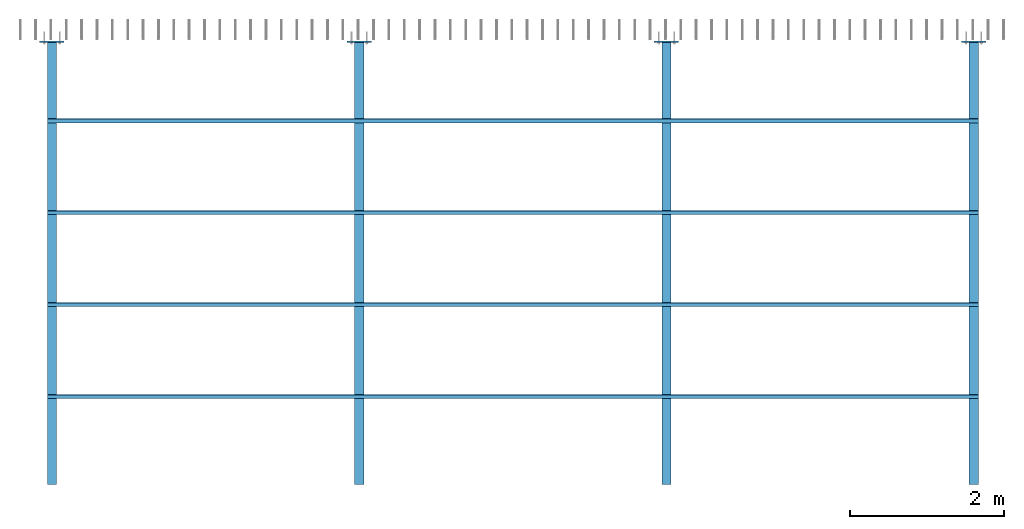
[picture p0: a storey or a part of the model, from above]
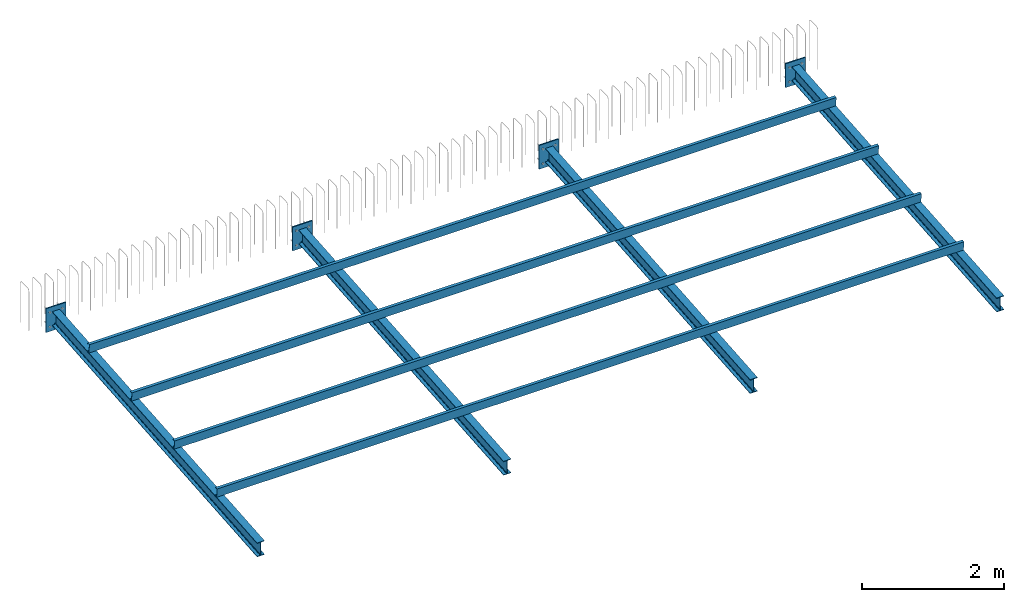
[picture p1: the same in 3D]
Properties of the parts of a building model (IFC4X3_ADD2), part 1 of 2

# File
Description: ViewDefinition [CoordinationView], RevitIdentifiers [ContentGUID: 4acb6c96-97fd-44d4-9711-2617cdbfe43d, VersionGUID: ed7fe11c-8d02-4497-8ebc-b011db3e209e, NumberOfSaves: 38], CoordinateReference [CoordinateBase: Shared Coordinates, ProjectSite: Internal]
File name: Complex_structure.ifc
Time: 2026-06-14T23:28:43+01:00
Written by: ODA SDAI 24.12
Made in: Autodesk Revit 25.4.0.32 (ENU) - IFC 25.4.0.27

# IfcProject, Complex structure
LongName: Project Name; Phase: Project Status

# IfcSite, Default
RefLatitude: 42, 21, 31, 181945; RefLongitude: -71, -3, -24, -263305; RefElevation: 0 mm
Pset_SiteCommon - Reference: Project Information
Pset_SpaceCommon - Reference: Project Information; IsExternal: no
Other - Category: Project Information; Client Name: Owner; Project Address: Enter address here; Project Issue Date: Issue Date; Project Name: Project Name; Project Number: Complex structure; Project Status: Project Status
Identity Data - Author: FJ; Building Name: Complex structure; Organization Name: QuantBIM

# IfcBuilding, Complex structure
LongName: Complex structure
Pset_BuildingCommon - Reference: Project Information; NumberOfStoreys: 8
Pset_BuildingElementProxyCommon - Reference: Project Information; IsExternal: no; sets with these values: 2
Pset_BuildingStoreyCommon - Reference: Project Information; sets with these values: 2
Other - Category: Project Information; Client Name: Owner; Project Address: Enter address here; Project Issue Date: Issue Date; Project Name: Project Name; Project Number: Complex structure; Project Status: Project Status
Identity Data - Author: FJ; Building Name: Complex structure; Organization Name: QuantBIM

# IfcBuildingStorey: Level:8mm Head (8)
In: Complex structure
Pset_BuildingStoreyCommon - Reference: 8mm Head
Pset_SpaceCommon - IsExternal: no; Reference: 8mm Head
Other - Category: Levels; Family: Level; Family and Type: Level: 8mm Head; Type: 8mm Head; Type Id: 305
Dimensions - Computation Height: 0 mm
Identity Data - Building Story: yes; Structural: no
Other(Type) - Category: Levels; Family Name: Level
Constraints(Type) - Elevation Base: Project Base Point
Graphics(Type) - Color: 0; Line Pattern: Centre; Line Weight: 1; Symbol: M_Level Head - Circle; Symbol at End 1 Default: no; Symbol at End 2 Default: yes
Identity Data(Type) - Type Name: 8mm Head
Name | LongName = Name | Elevation (mm) = Constraints, Elevation (mm)
Level -03 | Level -03 | -1200
Level -02 | Level -02 | -400
Level -01 | Level -01 | -200
Level 00 | Level 00 | 0
Level 01 | Level 01 | 3000
Level 02 | Level 02 | 4000
Level 03 | Level 03 | 4500
Level 04 | Level 04 | 5000

# IfcBeam: Construction_Beams-&-Lintels_Lindab_C-HU:Lindab C 150/1.5 (6)
Type - PredefinedType: JOIST; Material: Lindab_000_Galvanized
Type - Other - Category: Structural Framing; Family Name: Construction_Beams-&-Lintels_Lindab_C-HU
Type - Constraints - t: 1.5 mm
Type - Dimensions - Dimension: 150 mm; Flange1: 41 mm; Flange2: 47 mm; Stiffener: 15 mm; Thickness: 1.5 mm
Type - General - Brand url: http://www.lindab.com; Design country: Sweden; Edition number: 1; Manufacturer name: Lindab; Nominal height: 0 mm; Nominal width: 0 mm; Product family: Steel profiles; Product group: Purlins; Product SKU: c; QR code: http://bimobject.com/lindab/product/c; Region Europe: CZ, DK, HU, NO, PL, RO, SE, SK; Weight Net (Kg): 0
Type - Identity Data - Advanced_Design_Tool: http://www.lindab.com/lindabstructuraldesigner; Code Name: C; Installation instructions: http://www.lindab.com/global/Documents/Building%20Components%20Global/system_solution_roof_assembly_low.pdf; Manufacturer: Lindab; OmniClass Number: 23.25.30.11.14.14; OmniClass Title: Beams; Product certification: https://itsolution.lindab.com/lindabwebproductsdoc/pdf/documentation/building_components/uk/DoP/C_profiles.pdf; Product data url: https://bimobject.com/lindab/product/c; Product url: http://www.lindab.com/global/pro/downloads/certificates/pages/default.aspx#drilldown_guid:9fd857e6-9304-4852-8a1e-055bb2913d50;level:all;sub:4; Quick_Design_Tool: n/a; Section_Properties_Tool: http://ec3library.lindab.com; Technical description: http://ec3library.lindab.com/; Type Name: Lindab C 150/1.5; URL: http://www.lindab.com
Type - Materials and Finishes - Coating: n/a; Color: Natural Zinc; Material main: Galvanized steel; NCS: n/a; Quality: S350 Z275; RAL: n/a; Structural Material: Lindab_000_Galvanized
Type - Structural - Section Shape: 9
Type - Pset_BeamCommon - LoadBearing: yes
Type - Pset_ManufacturerTypeInformation - Manufacturer: Lindab
Pset_BeamCommon - IsExternal: no; Reference: Lindab C 150/1.5; Span: 12120 mm; Slope: 0 deg; Roll: 90 deg
Pset_EnvironmentalImpactIndicators - Reference: Lindab C 150/1.5; sets with these values: 2
Other - Family: Construction_Beams-&-Lintels_Lindab_C-HU; Family and Type: Construction_Beams-&-Lintels_Lindab_C-HU: Lindab C 150/1.5; LRT_Fastener: 0; Type: Lindab C 150/1.5; Type Id: 407912
Constraints - Orientation: Normal; Reference Level: Level -02; Cross-Section Rotation: 90 deg; Reference Level Elevation: -400 mm; Work Plane: Reference Plane : Szelemenek
Dimensions - Length: 12120 mm; Volume: 0.00476316 m3
Identity Data - Has Association: no
Phasing - Phase Created: New Construction
Structural - Stick Symbol Location: Center of Geometry; Cut Length: 12120 mm; Structural Usage: Joist; Weight: 0 kg
Geometric Position - End Extension: 0 mm; Join Status: Both joins enabled; Start Extension: 0 mm; y Justification: Origin; yz Justification: Uniform; z Justification: Top; z Offset Value: 0 mm; y Offset Value: -75 mm
Name (Construction_Beams-&-Lintels_Lindab_C-HU:Lindab C 150/1.5:...) | In | Host Id | End Level Offset (mm) = Start Level Offset (mm) | Elevation at Bottom (mm) | Elevation at Top (mm) | End Join Cutback (mm)
478069 | Level 02 | 478030 | 4805.5 | 4401.6 | 4554.98 | 12.7
478071 | Level 02 | 478030 | 4705.85 | 4301.94 | 4455.33 | 12.7
478073 | Level 02 | 478030 | 4606.19 | 4202.29 | 4355.68 | Geometric Position - Start Join Cutback: 12.7 mm
478180 | Level 02 | 478030 | 4506.54 | 4102.64 | 4256.02 | Geometric Position - Start Join Cutback: 12.7 mm
478247 | Level -02 |  | 4406.88 | 4002.98 | 4156.37 | 12.7 | Geometric Position - Start Join Cutback: 12.7 mm; Structural - End Attachment Type: End Elevation; Start Attachment Type: End Elevation
478413 | Level -02 |  | 4880.24 | 4476.34 | 4629.73 | 12.7

# IfcBeam: IPE:IPE140 (3)
In: Level 01
Type - PredefinedType: BEAM
Type - Other - Category: Structural Framing; Family Name: IPE
Type - Dimensions - Bolt Spacing: 0 mm
Type - Identity Data - Code Name: EURONORM 19-57; DIN 1025-5; Section Name Key: IPE140; Type Name: IPE140
Type - Structural - Section Shape: 6
Type - Structural Analysis - Torsional Moment of Inertia: 0 m4; Elastic Modulus strong axis: 0.0000773 m3; Elastic Modulus weak axis: 0.0000123 m3; Moment of Inertia strong axis: 0.00000541 m4; Moment of Inertia weak axis: 4.49e-07 m4; Nominal Weight: 126.506 kg/s2; Perimeter: 551 mm; Plastic Modulus strong axis: 0.0000883 m3; Plastic Modulus weak axis: 0.0000193 m3; Section Area: 0.00164 m2; Warping Constant: 0 m6
Type - Structural Section Geometry - Centroid Horizontal: 36.5 mm; Centroid Vertical: 70 mm; Flange Thickness: 6.9 mm; Height: 140 mm; Web Fillet: 7 mm; Web Thickness: 4.7 mm; Width: 73 mm
Type - Pset_BeamCommon - LoadBearing: yes
Description: BP{2A70AE7B-3EAF-463A-89AE-3075FF3C759C}; Material: Structural Steel - S235
Pset_BeamCommon - IsExternal: no; Roll: 0 deg; Slope: 0 deg; Reference: IPE140; Span: 4000 mm
Pset_EnvironmentalImpactIndicators - Reference: IPE140; sets with these values: 2
ProfileProperties - SectionFamily: {2A70AE7B-3EAF-463A-89AE-3075FF3C759C}BP; Section: BP{2A70AE7B-3EAF-463A-89AE-3075FF3C759C}
Other - Family: IPE; Family and Type: IPE: IPE140; Type: IPE140; Type Id: 399445
Constraints - Cross-Section Rotation: 0 deg; End Level Offset: 0 mm; Reference Level: Level 01; Start Level Offset: 0 mm; Orientation: Normal; Reference Level Elevation: 3000 mm; Work Plane: Level : Level 01
Dimensions - Elevation at Bottom: 2860 mm; Elevation at Top: 3000 mm; Length: 4000 mm; Volume: 0.00634454 m3
Identity Data - Has Association: no
Materials and Finishes - Structural Material: Structural Steel - S235
Phasing - Phase Created: New Construction
Structural - End Attachment Type: End Elevation; Start Attachment Type: End Elevation; Stick Symbol Location: Center of Geometry; Structural Usage: Girder; Coating: -; Cut Length: 3964 mm; Exact Weight: 52.246 kg; Paint Area: 2.18416 m2; Weight: 52.0389 kg
Geometric Position - Join Status: Both joins enabled; y Justification: Origin; y Offset Value: 0 mm; yz Justification: Uniform; z Justification: Top; z Offset Value: 0 mm
Name (IPE:IPE140:...)
399533
399563
399612

# IfcBeam: Round Bars:RB 20 (25)
Type - PredefinedType: BEAM; Material: Metal - Steel 50-355
Type - Other - Category: Structural Framing; Family Name: Round Bars
Type - Identity Data - Assembly Code: B10; Assembly Description: Superstructure; Code Name: EN 10060:2003; Section Name Key: RB 20; Type Name: RB 20
Type - Structural - Section Shape: 13
Type - Structural Analysis - Elastic Modulus strong axis: 0 m3; Elastic Modulus weak axis: 0 m3; Moment of Inertia strong axis: 0 m4; Moment of Inertia weak axis: 0 m4; Nominal Weight: 24.2224 kg/s2; Perimeter: 63 mm; Plastic Modulus strong axis: 0 m3; Plastic Modulus weak axis: 0 m3; Section Area: 0.000314 m2; Torsional Modulus: 0 m3; Torsional Moment of Inertia: 0 m4
Type - Structural Section Geometry - Centroid Horizontal: 10 mm; Centroid Vertical: 10 mm; Diameter: 20 mm
Type - Pset_BeamCommon - LoadBearing: yes
Classification: B10 Superstructure (Uniformat)
Pset_BeamCommon - IsExternal: no; Reference: RB 20; Roll: 0 deg
Pset_EnvironmentalImpactIndicators - Reference: RB 20; sets with these values: 2
Other - Family: Round Bars; Family and Type: Round Bars: RB 20; Type: RB 20; Type Id: 400683
Constraints - Cross-Section Rotation: 0 deg
Identity Data - Has Association: no
Materials and Finishes - Structural Material: Metal - Steel 50-355
Phasing - Phase Created: New Construction
Structural - Stick Symbol Location: Center of Geometry
Geometric Position - Join Status: Both joins enabled; y Justification: Origin; y Offset Value: 0 mm; yz Justification: Uniform; z Justification: Top; z Offset Value: 0 mm
Name (Round Bars:RB 20:...) | In | Span (mm) = Length (mm) | Slope (deg) | End Level Offset (mm) | Reference Level | Reference Level Elevation (mm) | Start Level Offset (mm) | Volume (m3) | Cut Length (mm) | End Attachment Type | Structural Usage | Weight (kg) | End Extension (mm) | End Join Cutback (mm) | Start Extension (mm) | Start Join Cutback (mm) | Orientation | Work Plane
473897 | Level 01 | 4123.1 | 14.0362 | 0 | Level 01 | 3000 | 1000 | 0.00123386 | 3927.7 | End Elevation | Girder | 9.68488 | 0 | 12.7 | 0 | 12.7 | Structural - Start Attachment Type: End Elevation
473987 | Level 01 | 4123.1 | 14.0362 | 1000 | Level 01 | 3000 | 0 | 0.00123386 | 3927.7 | End Elevation | Girder | 9.68488 | 0 | 12.7 | 0 | 12.7 | Structural - Start Attachment Type: End Elevation
474049 | Level 01 | 4123.1 | 14.0362 | 0 | Level 01 | 3000 | 1000 | 0.00123386 | 3927.7 | End Elevation | Girder | 9.68488 | 0 | 12.7 | 0 | 12.7 | Structural - Start Attachment Type: End Elevation
474135 | Level 01 | 4123.1 | 14.0362 | 1000 | Level 01 | 3000 | 0 | 0.00123386 | 3927.7 | End Elevation | Girder | 9.68488 | 0 | 12.7 | 0 | 12.7 | Structural - Start Attachment Type: End Elevation
474136 | Level 01 | 4123.1 | 14.0362 | 0 | Level 01 | 3000 | 1000 | 0.00123386 | 3927.7 | End Elevation | Girder | 9.68488 | 0 | 12.7 | 0 | 12.7 | Structural - Start Attachment Type: End Elevation
474175 | Level 01 | 4123.1 | 14.0362 | 1000 | Level 01 | 3000 | 0 | 0.00123386 | 3927.7 | End Elevation | Girder | 9.68488 | 0 | 12.7 | 0 | 12.7 | Structural - Start Attachment Type: End Elevation
474176 | Level 01 | 4123.1 | 14.0362 | 0 | Level 01 | 3000 | 1000 | 0.00123386 | 3927.7 | End Elevation | Girder | 9.68488 | 0 | 12.7 | 0 | 12.7 | Structural - Start Attachment Type: End Elevation
474847 | Level -02 | 4506.7 | 2.19258 | 4616.05 | Level -02 | -400 | 4443.63 | 0.00141575 | 4506.7 |  | Other | 11.1126 | 0 | -20.3646 | 0 | -20.1328 | Normal | Reference Plane : Merevitok
474897 | Level -02 | 4409 | 2.00187 | 4770.07 | Level -02 | -400 | 4616.05 | 0.00138509 | 4409.09 |  | Other | 10.8719 | 0 | -21.5679 | -4.91049 |  | Normal | Reference Plane : Merevitok
474934 | Level -02 | 4409 | 2.00187 | 4616.05 | Level -02 | -400 | 4770.07 | 0.00138506 | 4409 |  | Other | 10.8717 | 0 | -20.8261 | 0 |  | Normal | Reference Plane : Merevitok
474989 | Level -02 | 4466.6 | 2.11781 | 4450.99 | Level -02 | -400 | 4616.05 | 0.00140317 | 4466.63 |  | Other | 11.0138 | -4.96898 |  | 0 | -20.8261 | Normal | Reference Plane : Merevitok
475036 | Level -02 | 4466.6 | 2.11781 | 4285.93 | Level -02 | -400 | 4450.99 | 0.00140316 | 4466.6 | End Elevation | Other | 11.0137 | 0 | -19.7362 | 0 | -20.1248 | Normal | Reference Plane : Merevitok
475112 | Level -02 | 4427.8 | 2.04105 | 4285.93 | Level -02 | -400 | 4443.63 | 0.00139128 | 4428.8 | End Elevation | Other | 10.9205 | 0 | -21.6534 | 0 | -20.1328 | Normal | Reference Plane : Merevitok
475159 | Level -02 | 4409 | 2.00187 | 4770.07 | Level -02 | -400 | 4616.05 | 0.00138507 | 4409.03 |  | Other | 10.8717 | -21.5679 |  | 0 | -20.3646 | Normal | Reference Plane : Merevitok
475161 | Level -02 | 4466.6 | 2.11781 | 4450.99 | Level -02 | -400 | 4616.05 | 0.00140316 | 4466.6 |  | Other | 11.0137 | 0 | -20.1248 | 0 | -20.8261 | Normal | Reference Plane : Merevitok
475199 | Level -02 | 4506.7 | 2.19258 | 4616.05 | Level -02 | -400 | 4443.63 | 0.00141575 | 4506.7 |  | Other | 11.1126 | 0 | -20.3646 | 0 | -20.1328 | Normal | Reference Plane : Merevitok
475201 | Level -02 | 4409 | 2.00187 | 4616.05 | Level -02 | -400 | 4770.07 | 0.00138509 | 4409.1 |  | Other | 10.8719 | -4.80167 |  | 0 | -7.63229 | Normal | Reference Plane : Merevitok
475337 | Level -02 | 4506.7 | 2.19258 | 4616.05 | Level -02 | -400 | 4443.63 | 0.00141575 | 4506.7 |  | Other | 11.1126 | 0 | -20.3646 | 0 | -20.1328 | Normal | Reference Plane : Merevitok
475338 | Level -02 | 4409 | 2.00187 | 4616.05 | Level -02 | -400 | 4770.07 | 0.00138506 | 4409 |  | Other | 10.8717 | 0 | -20.8261 | -21.5679 | -7.63229 | Normal | Reference Plane : Merevitok
475387 | Level -02 | 4409 | 2.00187 | 4770.07 | Level -02 | -400 | 4616.05 | 0.00138506 | 4409 |  | Other | 10.8717 | 0 |  | 0 | -20.3646 | Normal | Reference Plane : Merevitok
475388 | Level -02 | 4466.6 | 2.11781 | 4450.99 | Level -02 | -400 | 4616.05 | 0.00140316 | 4466.6 |  | Other | 11.0137 | 0 | -20.1248 | 0 | -20.8261 | Normal | Reference Plane : Merevitok
475510 | Level -02 | 4466.6 | 2.11781 | 4285.93 | Level -02 | -400 | 4450.99 | 0.00140316 | 4466.6 | End Elevation | Other | 11.0137 | 0 | -19.7362 | 0 | -20.1248 | Normal | Reference Plane : Merevitok
475511 | Level -02 | 4427.8 | 2.04105 | 4285.93 | Level -02 | -400 | 4443.63 | 0.00139097 | 4427.8 | End Elevation | Other | 10.918 | 0 | -20.6607 | 0 | -20.1328 | Normal | Reference Plane : Merevitok
475529 | Level -02 | 4466.6 | 2.11781 | 4285.93 | Level -02 | -400 | 4450.99 | 0.0014035 | 4467.7 | End Elevation | Other | 11.0164 | 0 | -20.8126 | 0 | -20.1248 | Normal | Reference Plane : Merevitok
475530 | Level -02 | 4427.8 | 2.04105 | 4285.93 | Level -02 | -400 | 4443.63 | 0.00139097 | 4427.8 | End Elevation | Other | 10.918 | 0 | -20.6607 | 0 | -20.1328 | Normal | Reference Plane : Merevitok

# IfcBuildingElementProxy: Foundation Slab:Foundation Slab 200mm, Foundation Slab:Foundation Slab 200mm:356789
In: Level -02
Material: Concrete, Cast In Situ 200 mm
Other - Category: Structural Foundations; Family: Foundation Slab; Family and Type: Foundation Slab: Foundation Slab 200mm; Type: Foundation Slab 200mm; Type Id: 356880
Constraints - Level: Level -02; Related to Mass: no; Height Offset From Level: 200 mm
Dimensions - Area: 82.81 m2; Core Thickness: 200 mm; Elevation at Bottom: -400 mm; Elevation at Bottom Core: -400 mm; Elevation at Bottom Survey: -400 mm; Elevation at Top: -200 mm; Elevation at Top Core: -200 mm; Elevation at Top Survey: -200 mm; Length: 6370 mm; Perimeter: 38740 mm; Thickness: 200 mm; Volume: 16.562 m3; Width: 13000 mm
Identity Data - Has Association: no
Phasing - Phase Created: New Construction
Structural - Rebar Cover - Other Faces: Rebar Cover 1 <25 mm>; Structural: yes; Estimated Reinforcement Volume: 0.154037 m3; Rebar Cover - Bottom Face: Rebar Cover 1 <25 mm>; Rebar Cover - Top Face: Rebar Cover 1 <25 mm>
Other(Type) - Category: Structural Foundations; Family Name: Foundation Slab
Construction(Type) - Default Thickness: 200 mm
Dimensions(Type) - Foundation Thickness: 200 mm
Graphics(Type) - Coarse Scale Fill Color: 0
Identity Data(Type) - Type Name: Foundation Slab 200mm
Materials and Finishes(Type) - Structural Material: Concrete, Cast In Situ
Analytical Properties(Type) - Absorptance: 0.7; Roughness: 3; Heat Transfer Coefficient (U): 5.23 kg/K/s3; Thermal Mass: 302220 kg/K/s2; Thermal Resistance (R): 0.191205 s3*K/kg

# IfcColumn: HE-A Column:HEA160 (4)
In: Level -01
Type - PredefinedType: COLUMN; Material: Structural Steel - S235
Type - Other - Category: Structural Columns; Family Name: HE-A Column
Type - Dimensions - Bolt Diameter: 0 mm; Bolt Spacing: 99 mm
Type - Identity Data - Code Name: EURONORM 53-62; DIN 1025-3; Section Name Key: HEA160; Type Name: HEA160
Type - Structural - Section Shape: 8
Type - Structural Analysis - Torsional Moment of Inertia: 0 m4; Warping Constant: 0 m6; Elastic Modulus strong axis: 0.00022 m3; Elastic Modulus weak axis: 0.0000769 m3; Moment of Inertia strong axis: 0.0000167 m4; Moment of Inertia weak axis: 0.00000616 m4; Nominal Weight: 298.122 kg/s2; Perimeter: 906 mm; Plastic Modulus strong axis: 0.0002451 m3; Plastic Modulus weak axis: 0.0001176 m3; Section Area: 0.00388 m2
Type - Structural Section Geometry - Centroid Horizontal: 80 mm; Centroid Vertical: 76 mm; Flange Thickness: 9 mm; Height: 152 mm; Web Fillet: 15 mm; Web Thickness: 6 mm; Width: 160 mm
Type - Pset_ColumnCommon - LoadBearing: yes
Description: BP{7F9EABB0-F8C3-481F-A3BD-D3AADC916256}
Pset_ColumnCommon - IsExternal: no; Reference: HEA160
Pset_EnvironmentalImpactIndicators - Reference: HEA160; sets with these values: 2
ProfileProperties - SectionFamily: {7F9EABB0-F8C3-481F-A3BD-D3AADC916256}BP; Section: BP{7F9EABB0-F8C3-481F-A3BD-D3AADC916256}
Other - Family: HE-A Column; Family and Type: HE-A Column: HEA160; Type: HEA160; Type Id: 391126
Constraints - Moves With Grids: yes; Base Offset: 0 mm; Base Level: Level -01; Column Style: Vertical; Level: Level -01; Top Level: Level 02; Top Offset: 0 mm
Dimensions - Length: 4200 mm; Volume: 0.0153423 m3
Identity Data - Has Association: no
Materials and Finishes - Structural Material: Structural Steel - S235
Phasing - Phase Created: New Construction
Structural - Coating: -; Cut Length: 4170.9 mm; Exact Weight: 129.688 kg; Paint Area: 3.77883 m2; Weight: 130.446 kg
Name (HE-A Column:HEA160:...) | Column Location Mark
362460 | B-3
362442 | B-2
359729 | B-1
362476 | B-4

# IfcElementAssembly: Structural Beam System:Structural Framing System, Structural Beam System:Structural Framing System:478030
In: Level 02
PredefinedType: BEAM_GRID
Pset_ElementAssemblyCommon - Reference: Structural Framing System; sets with these values: 2
Other - Category: Structural Beam Systems; Family: Structural Beam System; Family and Type: Structural Beam System: Structural Framing System; Type: Structural Framing System; Type Id: 49026
Constraints - 3D: no; Work Plane: Reference Plane : Szelemenek
Identity Data - Tag new members in view: Structural Plan: Level 03
Phasing - Phase Created: New Construction
Pattern - Beam Type: Round Bars : RB 20; Beam Type (No Family Name): RB 20; Centerline Spacing: 1200 mm; Fixed Spacing: 1200 mm; Justification: Center; Layout Rule: Fixed Distance
Other(Type) - Category: Structural Beam Systems; Family Name: Structural Beam System
Identity Data(Type) - Type Name: Structural Framing System

# IfcFooting: Footing-Rectangular:1000 x 1000 x 800mm (4)
In: Level -02
Type - Material: Concrete - Cast-in-Place Concrete
Type - Other - Category: Structural Foundations; Family Name: Footing-Rectangular
Type - Dimensions - Foundation Thickness: 800 mm; Length: 1000 mm; Width: 1000 mm
Type - Identity Data - Type Name: 1000 x 1000 x 800mm
Pset_EnvironmentalImpactIndicators - Reference: 1000 x 1000 x 800mm; sets with these values: 4
Other - Family: Footing-Rectangular; Family and Type: Footing-Rectangular: 1000 x 1000 x 800mm; Type: 1000 x 1000 x 800mm; Type Id: 356662
Constraints - Height Offset From Level: 0 mm; Host: Level : Level -02; Level: Level -02; Moves With Grids: yes
Dimensions - Area: 1 m2; Elevation at Bottom: -1200 mm; Elevation at Bottom Survey: -1200 mm; Elevation at Top: -400 mm; Elevation at Top Survey: -400 mm; Volume: 0.8 m3
Identity Data - Has Association: no
Materials and Finishes - Structural Material: Concrete - Cast-in-Place Concrete
Phasing - Phase Created: New Construction
Structural - Rebar Cover - Bottom Face: Rebar Cover 2 <40 mm>; Rebar Cover - Other Faces: Rebar Cover 2 <40 mm>
Name (Footing-Rectangular:1000 x 1000 x 800mm:...) | Estimated Reinforcement Volume (m3)
355354 | 0.00298749
355619 | 0.00654463
355704 | 0.00477191
355767 | 0.00477191

# IfcFooting: Wall Foundation:Bearing Footing 800 x 800mm, Wall Foundation:Bearing Footing 800 x 800mm:356264
In: Level -03
Type - PredefinedType: STRIP_FOOTING
Type - Other - Category: Structural Foundations; Family Name: Wall Foundation
Type - Dimensions - Default End Extension Length: 0 mm; Do Not Break At Inserts: no; Foundation Thickness: 800 mm; Width: 800 mm
Type - Identity Data - Type Name: Bearing Footing 800 x 800mm
Type - Materials and Finishes - Structural Material: Concrete, Cast In Situ
Type - Structural - Structural Usage: Bearing
Material: Concrete, Cast In Situ
Pset_EnvironmentalImpactIndicators - Reference: Bearing Footing 800 x 800mm; sets with these values: 4
Other - Family: Wall Foundation; Family and Type: Wall Foundation: Bearing Footing 800 x 800mm; Type: Bearing Footing 800 x 800mm; Type Id: 355989
Constraints - Eccentricity: 0 mm
Dimensions - Area: 10.4 m2; Elevation at Bottom: -1200 mm; Elevation at Bottom Survey: -1200 mm; Elevation at Top: -400 mm; Elevation at Top Survey: -400 mm; Length: 13000 mm; Volume: 8.32 m3
Identity Data - Has Association: no
Phasing - Phase Created: New Construction
Structural - Rebar Cover - Bottom Face: Rebar Cover 2 <40 mm>; Rebar Cover - Other Faces: Rebar Cover 2 <40 mm>; Estimated Reinforcement Volume: 0.06958 m3; Rebar Cover - Top Face: Rebar Cover 2 <40 mm>

# IfcMechanicalFastener: Anchor_Bolt#1 (8)
Name | In | NominalDiameter (mm) | NominalLength (mm)
4 x  | Level 02 | 20 | 170
4 x  | Level -03 | 19.05 | 304.8

# IfcMechanicalFastener: Bolt#1 (10)
Name | In | NominalDiameter (mm) | NominalLength (mm)
4 x  | Level 01 | 16 | 55
6 x  | Level 00 | 12 | 45

# IfcMechanicalFastener: Bolt#2 (10)
Name | In | NominalDiameter (mm) | NominalLength (mm)
4 x  | Level 01 | 16 | 55
6 x  | Level 00 | 12 | 45

# IfcMechanicalFastener: Bolt#3 (4)
In: Level 01
NominalDiameter: 16 mm; NominalLength: 55 mm

# IfcMechanicalFastener: Bolt#4 (4)
In: Level 01
NominalDiameter: 16 mm; NominalLength: 55 mm

# IfcMechanicalFastener: Bolt#5 (10)
Name | In | NominalDiameter (mm) | NominalLength (mm)
4 x  | Level 01 | 16 | 55
6 x  | Level 00 | 12 | 45

# IfcMechanicalFastener: Bolt#6 (10)
Name | In | NominalDiameter (mm) | NominalLength (mm)
4 x  | Level 01 | 16 | 55
6 x  | Level 00 | 12 | 45

# IfcMechanicalFastener: Bolt#7 (4)
In: Level 01
NominalDiameter: 16 mm; NominalLength: 55 mm

# IfcMechanicalFastener: Bolt#8 (4)
In: Level 01
NominalDiameter: 16 mm; NominalLength: 55 mm

# IfcMember: Haunch (4)
In: Level 01
Description: BP{96DF68AE-9A4C-428B-985C-CF8941B73864}
ProfileProperties - SectionFamily: {96DF68AE-9A4C-428B-985C-CF8941B73864}BP; Section: BP{96DF68AE-9A4C-428B-985C-CF8941B73864}

# IfcMember: IPE-Beams:IPE240 (4)
In: Level 02
Type - PredefinedType: MEMBER; Material: Structural Steel - S235
Type - Other - Category: Structural Framing; Family Name: IPE-Beams
Type - Dimensions - bf: 120 mm; d: 240 mm; k: 24.8 mm; tf: 9.8 mm; tr: 15 mm; tw: 6.2 mm
Type - Identity Data - Type Name: IPE240
Type - Structural - A: 0.00391162 m2; Section Shape: 0; W: 0.301125
Type - Pset_MemberCommon - LoadBearing: yes
Description: BP{96DF68AE-9A4C-428B-985C-CF8941B73864}
Pset_EnvironmentalImpactIndicators - Reference: IPE240
Pset_MemberCommon - IsExternal: no; Roll: 0 deg; Reference: IPE240; Span: 5870 mm; Slope: 4.76387 deg
ProfileProperties - SectionFamily: {96DF68AE-9A4C-428B-985C-CF8941B73864}BP; Section: BP{96DF68AE-9A4C-428B-985C-CF8941B73864}
Other - Family: IPE-Beams; Family and Type: IPE-Beams: IPE240; Type: IPE240; Type Id: 362347
Constraints - Cross-Section Rotation: 0 deg; Start Level Offset: 0 mm; End Level Offset: 487.5 mm; Reference Level: Level 02; Reference Level Elevation: 4000 mm
Dimensions - Length: 5870 mm; Volume: 0.0214703 m3
Identity Data - Has Association: no
Materials and Finishes - Structural Material: Structural Steel - S235
Phasing - Phase Created: New Construction
Structural - Stick Symbol Location: Center of Geometry; Structural Usage: Girder; Weight: 0 kg; Coating: -; Cut Length: 5793.94 mm; Exact Weight: 181.626 kg; Paint Area: 5.49034 m2
Geometric Position - Join Status: Both joins enabled; y Justification: Origin; y Offset Value: 0 mm; yz Justification: Uniform; z Justification: Top; z Offset Value: 0 mm
Name (IPE-Beams:IPE240:...)
464337 | Structural - Start Attachment Type: End Elevation
473112
473148
473183 | Structural - Start Attachment Type: End Elevation

# IfcOpeningElement, Basic Wall:Generic - 300mm:6291
In: Level -02
PredefinedType: OPENING
Pset_EnvironmentalImpactIndicators - Reference: Generic - 300mm; sets with these values: 2
Other - Category: Lines: <Sketch>
Dimensions - Length: 3200 mm

# IfcPlate: Baseplate (8)
Description: -
Pset_PlateCommon - Reference: Not defined; IsExternal: no; LoadBearing: no
Name | In | Material
4 x Baseplate | Level 02 | Metal Stud Layer 20 mm
4 x Baseplate | Level -02 | Metal Stud Layer 25.4 mm

# IfcPlate: Coverplate (4)
In: Level 01
Description: -; Material: Metal Stud Layer 10 mm
Pset_PlateCommon - Reference: Not defined; IsExternal: no; LoadBearing: no

# IfcPlate: Endplate (10)
Description: -
Pset_PlateCommon - Reference: Not defined; IsExternal: no; LoadBearing: no
Name | In | Material
4 x Endplate | Level 01 | Metal Stud Layer 20 mm
6 x Endplate | Level 00 | Metal Stud Layer 15 mm

# IfcPlate: Stiffener#14 (4)
In: Level 01
Description: -; Material: Metal Stud Layer 10 mm
Pset_PlateCommon - Reference: Not defined; IsExternal: no; LoadBearing: no

# IfcPlate: Stiffener#2 (8)
In: Level 01
Description: -; Material: Metal Stud Layer 10 mm
Pset_PlateCommon - Reference: Not defined; IsExternal: no; LoadBearing: no

# IfcPlate: Stiffener#3 (4)
In: Level 01
Description: -; Material: Metal Stud Layer 10 mm
Pset_PlateCommon - Reference: Not defined; IsExternal: no; LoadBearing: no

# IfcPlate: Stiffener#5 (4)
In: Level -01
Description: -; Material: Metal Stud Layer 20 mm
Pset_PlateCommon - Reference: Not defined; IsExternal: no; LoadBearing: no

# IfcPlate: Stiffener#6 (4)
In: Level -01
Description: -; Material: Metal Stud Layer 20 mm
Pset_PlateCommon - Reference: Not defined; IsExternal: no; LoadBearing: no

# IfcReinforcingBar: Rebar Bar:10mm (34)
Type - Other - Category: Structural Rebar; Family Name: Rebar Bar
Type - Construction - Deformation: Deformed
Type - Dimensions - Bar Diameter: 10 mm; Maximum Bend Radius: 18000 mm; Model Bar Diameter: 10 mm; Standard Bend Diameter: 80 mm; Standard Hook Bend Diameter: 80 mm; Stirrup/Tie Bend Diameter: 50 mm
Type - Identity Data - Type Name: 10mm
Type - Materials and Finishes - Material: Steel Rebar - B500A, B or C
Material: Steel Rebar - B500A, B or C
Pset_ElementComponentCommon - Reference: 10mm; sets with these values: 2
Rebar Schedule - Deformation: Deformed; G: 0 mm; Geometry: Shape Driven; Bar Diameter: 10 mm; Family: Rebar Bar; Family and Type: Rebar Bar: 10mm; Material: Steel Rebar - B500A, B or C
Other - Family: Rebar Bar; Family and Type: Rebar Bar: 10mm; Type: 10mm; Type Id: 375225
Construction - Geometry: Shape Driven; Hook Rotation At End: 0 deg; Hook Rotation At Start: 0 deg; Modified Rebar Set: no; Override Hook Lengths: no; Rebar Constraint Status: Enabled; Staggered Set: no
Dimensions - G: 0 mm; H: 0 mm; J: 0 mm
Phasing - Phase Created: New Construction
Rebar Set - Distribution Type: Uniform; Layout Rule: Number with Spacing
Name (Rebar Bar:10mm :...) | In | Rebar Schedule, A (mm) = Dimensions, A (mm) | Rebar Schedule, B (mm) = Dimensions, B (mm) | Rebar Schedule, Bar Length (mm) = Dimensions, Bar Length (mm) = Maximum Bar Length (mm) = Minimum Bar Length (mm) | Rebar Schedule, C (mm) = Dimensions, C (mm) | Rebar Schedule, D (mm) = Dimensions, D (mm) | Rebar Schedule, E (mm) = Dimensions, E (mm) | Rebar Schedule, F (mm) = Dimensions, F (mm) | Rebar Schedule, H1 (mm) = Rebar Schedule, H2 (mm) = Dimensions, H1 (mm) = Dimensions, H2 (mm) | Bend Diameter (mm) | Maximum Rebar Number = Minimum Rebar Number = Rebar Number | Schedule Mark | Shape | Style | R (mm) | Length of each bar (mm) | Total Bar Length (mm) | Host Category | Quantity = Quantity By Rebar Set | Spacing (mm) | Estimated Reinforcement Volume (m3) = Reinforcement Volume (m3)
 Shape 52:375177 | Level -03 | 940 | 939.3 | 3881.34 | 95 | 95 | 1180 | 1000 | 95.6858 | 50 | 3 | 1 | 52 | Stirrup / Tie | 0 | 3881.1 | 7762.69 | Structural Foundation | 2 | 200 | 0.00060968 | Rebar Schedule - Hook At End: Stirrup/Tie Seismic - 135 deg.; Hook At Start: Stirrup/Tie Seismic - 135 deg.; Construction - Hook At End: Stirrup/Tie Seismic - 135 deg.; Hook At Start: Stirrup/Tie Seismic - 135 deg.; Stirrup/Tie Attachment: Interior Face of Cover Reference; Dimensions - Standard Bend Diameter: 50 mm
 Shape 21:377551 | Level -03 | 400 | 720 | 1461.37 | 400 | 0 | 0 | 0 | 0 | 80 | 7 | 2 | 21 | Standard | 0 | 1460 | 94989.2 | Structural Foundation | 65 | 200 | 0.00746043
 Shape 52:379061 | Level -03 | 935 | 244 | 2480.74 | 95 | 95 | 1180 | 1000 | 95.6858 | 50 | 11 | 2 | 52 | Stirrup / Tie | 0 | 2480.5 | 86826 | Structural Foundation | 35 | 200 | 0.0068193 | Rebar Schedule - Hook At End: Stirrup/Tie Seismic - 135 deg.; Hook At Start: Stirrup/Tie Seismic - 135 deg.; Construction - Hook At End: Stirrup/Tie Seismic - 135 deg.; Hook At Start: Stirrup/Tie Seismic - 135 deg.; Stirrup/Tie Attachment: Interior Face of Cover Reference; Dimensions - Standard Bend Diameter: 50 mm
 Shape 21:381630 | Level -03 | 198 | 920 | 1257.37 | 198 | 0 | 0 | 0 | 0 | 80 | 19 | 1 | 21 | Standard | 0 | 1256 | 2514.74 | Structural Foundation | 2 | 400 | 0.000197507
 Shape 21:381802 | Level -03 | 199 | 918 | 1257.37 | 199 | 0 | 0 | 0 | 0 | 80 | 18 | 1 | 21 | Standard | 0 | 1256 | 2514.74 | Structural Foundation | 2 | 400 | 0.000197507
 Shape 52:381964 | Level -03 | 443.637 | 440 | 1890.02 | 95 | 95 | 1180 | 1000 | 95.6858 | 50 | 17 | 1 | 52 | Stirrup / Tie | 0 | 1889.77 | 3780.03 | Structural Foundation | 2 | 200 | 0.000296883 | Rebar Schedule - Hook At End: Stirrup/Tie Seismic - 135 deg.; Hook At Start: Stirrup/Tie Seismic - 135 deg.; Construction - Hook At End: Stirrup/Tie Seismic - 135 deg.; Hook At Start: Stirrup/Tie Seismic - 135 deg.; Stirrup/Tie Attachment: Interior Face of Cover Reference; Dimensions - Standard Bend Diameter: 50 mm
 Shape 12:383578 | Level -02 | 120 | 6319 | 6405.39 | 0 | 0 | 0 | 0 | 0 | 80 | 22 | 3 | 12 | Standard | 50 | 6405.5 | 211378 | Structural Foundation | 33 | 400 | 0.0166016
 Shape 12:384593 | Level -02 | 150 | 7000 | 7116.39 | 0 | 0 | 0 | 0 | 0 | 80 | 23 | 3 | 12 | Standard | 50 | 7116.5 | 113862 | Structural Foundation | 16 | 400 | 0.00894272
 Shape 12:385066 | Level -02 | 120 | 7000 | 7086.39 | 0 | 0 | 0 | 0 | 0 | 80 | 53 | 3 | 12 | Standard | 50 | 7086.5 | 113382 | Structural Foundation | 16 | 400 | 0.00890503
 Shape 52:385731 | Level -03 | 940 | 939.3 | 3881.34 | 95 | 95 | 1180 | 1000 | 95.6858 | 50 | 3 | 1 | 52 | Stirrup / Tie | 0 | 3881.1 | 7762.69 | Structural Foundation | 2 | 200 | 0.00060968 | Rebar Schedule - Hook At End: Stirrup/Tie Seismic - 135 deg.; Hook At Start: Stirrup/Tie Seismic - 135 deg.; Construction - Hook At End: Stirrup/Tie Seismic - 135 deg.; Hook At Start: Stirrup/Tie Seismic - 135 deg.; Stirrup/Tie Attachment: Interior Face of Cover Reference; Dimensions - Standard Bend Diameter: 50 mm
 Shape 21:385734 | Level -03 | 198 | 920 | 1257.37 | 198 | 0 | 0 | 0 | 0 | 80 | 19 | 1 | 21 | Standard | 0 | 1256 | 2514.74 | Structural Foundation | 2 | 400 | 0.000197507
 Shape 21:385735 | Level -03 | 199 | 918 | 1257.37 | 199 | 0 | 0 | 0 | 0 | 80 | 18 | 1 | 21 | Standard | 0 | 1256 | 2514.74 | Structural Foundation | 2 | 300 | 0.000197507
 Shape 52:385736 | Level -03 | 443.637 | 440 | 1890.02 | 95 | 95 | 1180 | 1000 | 95.6858 | 50 | 17 | 1 | 52 | Stirrup / Tie | 0 | 1889.77 | 3780.03 | Structural Foundation | 2 | 200 | 0.000296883 | Rebar Schedule - Hook At End: Stirrup/Tie Seismic - 135 deg.; Hook At Start: Stirrup/Tie Seismic - 135 deg.; Construction - Hook At End: Stirrup/Tie Seismic - 135 deg.; Hook At Start: Stirrup/Tie Seismic - 135 deg.; Stirrup/Tie Attachment: Interior Face of Cover Reference; Dimensions - Standard Bend Diameter: 50 mm
 Shape 52:385758 | Level -03 | 940 | 939.3 | 3881.34 | 95 | 95 | 1180 | 1000 | 95.6858 | 50 | 3 | 1 | 52 | Stirrup / Tie | 0 | 3881.1 | 7762.69 | Structural Foundation | 2 | 200 | 0.00060968 | Rebar Schedule - Hook At End: Stirrup/Tie Seismic - 135 deg.; Hook At Start: Stirrup/Tie Seismic - 135 deg.; Construction - Hook At End: Stirrup/Tie Seismic - 135 deg.; Hook At Start: Stirrup/Tie Seismic - 135 deg.; Stirrup/Tie Attachment: Interior Face of Cover Reference; Dimensions - Standard Bend Diameter: 50 mm
 Shape 21:385761 | Level -03 | 198 | 920 | 1257.37 | 198 | 0 | 0 | 0 | 0 | 80 | 19 | 1 | 21 | Standard | 0 | 1256 | 2514.74 | Structural Foundation | 2 | 400 | 0.000197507
 Shape 21:385762 | Level -03 | 199 | 918 | 1257.37 | 199 | 0 | 0 | 0 | 0 | 80 | 18 | 1 | 21 | Standard | 0 | 1256 | 2514.74 | Structural Foundation | 2 | 400 | 0.000197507
 Shape 52:385763 | Level -03 | 443.637 | 440 | 1890.02 | 95 | 95 | 1180 | 1000 | 95.6858 | 50 | 17 | 1 | 52 | Stirrup / Tie | 0 | 1889.77 | 3780.03 | Structural Foundation | 2 | 200 | 0.000296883 | Rebar Schedule - Hook At End: Stirrup/Tie Seismic - 135 deg.; Hook At Start: Stirrup/Tie Seismic - 135 deg.; Construction - Hook At End: Stirrup/Tie Seismic - 135 deg.; Hook At Start: Stirrup/Tie Seismic - 135 deg.; Stirrup/Tie Attachment: Interior Face of Cover Reference; Dimensions - Standard Bend Diameter: 50 mm
 Shape 52:385781 | Level -03 | 940 | 939.3 | 3881.34 | 95 | 95 | 1180 | 1000 | 95.6858 | 50 | 3 | 1 | 52 | Stirrup / Tie | 0 | 3881.1 | 7762.69 | Structural Foundation | 2 | 200 | 0.00060968 | Rebar Schedule - Hook At End: Stirrup/Tie Seismic - 135 deg.; Hook At Start: Stirrup/Tie Seismic - 135 deg.; Construction - Hook At End: Stirrup/Tie Seismic - 135 deg.; Hook At Start: Stirrup/Tie Seismic - 135 deg.; Stirrup/Tie Attachment: Interior Face of Cover Reference; Dimensions - Standard Bend Diameter: 50 mm
 Shape 21:385784 | Level -03 | 198 | 920 | 1257.37 | 198 | 0 | 0 | 0 | 0 | 80 | 19 | 1 | 21 | Standard | 0 | 1256 | 2514.74 | Structural Foundation | 2 | 400 | 0.000197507
 Shape 21:385785 | Level -03 | 199 | 918 | 1257.37 | 199 | 0 | 0 | 0 | 0 | 80 | 18 | 1 | 21 | Standard | 0 | 1256 | 2514.74 | Structural Foundation | 2 | 400 | 0.000197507
 Shape 52:385786 | Level -03 | 443.637 | 440 | 1890.02 | 95 | 95 | 1180 | 1000 | 95.6858 | 50 | 17 | 1 | 52 | Stirrup / Tie | 0 | 1889.77 | 3780.03 | Structural Foundation | 2 | 200 | 0.000296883 | Rebar Schedule - Hook At End: Stirrup/Tie Seismic - 135 deg.; Hook At Start: Stirrup/Tie Seismic - 135 deg.; Construction - Hook At End: Stirrup/Tie Seismic - 135 deg.; Hook At Start: Stirrup/Tie Seismic - 135 deg.; Stirrup/Tie Attachment: Interior Face of Cover Reference; Dimensions - Standard Bend Diameter: 50 mm
 Shape 21:387282 | Level 02 | 720 | 250 | 1631.37 | 720 | 0 | 0 | 0 | 0 | 80 | 31 | 4 | 21 | Standard | 0 | 1630 | 106039 | Wall | 65 | 200 | 0.0083283
 Shape 21:391922 | Level -01 | 720 | 224 | 1605.37 | 720 | 0 | 0 | 0 | 0 | 80 | 42 | 4 | 21 | Standard | 0 | 1604 | 41739.7 | Wall | 26 | 200 | 0.00327823
 Shape 21:392317 | Level 01 | 720 | 224 | 1605.37 | 720 | 0 | 0 | 0 | 0 | 80 | 42 | 4 | 21 | Standard | 0 | 1604 | 16053.7 | Wall | 10 | 200 | 0.00126086
 Shape 21:392416 | Level -01 | 720 | 224 | 1605.37 | 720 | 0 | 0 | 0 | 0 | 80 | 42 | 4 | 21 | Standard | 0 | 1604 | 25685.9 | Wall | 16 | 200 | 0.00201737
 Shape 00:395647 | Level -03 | 12000 | 0 | 12000 | 0 | 0 | 0 | 0 | 0 | 80 | 48 | 2 | 00 | Standard | 0 | 12000 | 48000 | Structural Foundation | 4 | 200 | 0.00376991
 Shape 00:395772 | Level -03 | 12000 | 0 | 12000 | 0 | 0 | 0 | 0 | 0 | 80 | 48 | 2 | 00 | Standard | 0 | 12000 | 48000 | Structural Foundation | 4 | 200 | 0.00376991
 Shape 00:395807 | Level -02 | 12000 | 0 | 12000 | 0 | 0 | 0 | 0 | 0 | 80 | 48 | 2 | 00 | Standard | 0 | 12000 | 48000 | Structural Foundation | 4 | 200 | 0.00376991
 Shape 21:395938 | Level -03 | 910 | 721.873 | 2483.25 | 910 | 0 | 0 | 0 | 0 | 80 | 50 | 2 | 21 | Standard | 0 | 2481.87 | 9932.98 | Structural Foundation | 4 | 200 | 0.000780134
 Shape 21:396326 | Level -03 | 900 | 706 | 2447.37 | 900 | 0 | 0 | 0 | 0 | 80 | 49 | 2 | 21 | Standard | 0 | 2446 | 9789.49 | Structural Foundation | 4 | 200 | 0.000768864
 Shape 21:396605 | Level -03 | 910 | 721.873 | 2483.25 | 910 | 0 | 0 | 0 | 0 | 80 | 50 | 2 | 21 | Standard | 0 | 2481.87 | 9932.98 | Structural Foundation | 4 | 200 | 0.000780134
 Shape 21:396606 | Level -03 | 900 | 706 | 2447.37 | 900 | 0 | 0 | 0 | 0 | 80 | 49 | 2 | 21 | Standard | 0 | 2446 | 9789.49 | Structural Foundation | 4 | 200 | 0.000768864
 Shape 12:396876 | Level -02 | 140 | 7000 | 7106.39 | 0 | 0 | 0 | 0 | 0 | 80 | 26 | 3 | 12 | Standard | 50 | 7106.5 | 14212.8 | Structural Foundation | 2 | 180 | 0.00111627
 Shape 12:397622 | Level -02 | 140 | 7000 | 7106.39 | 0 | 0 | 0 | 0 | 0 | 80 | 26 | 3 | 12 | Standard | 50 | 7106.5 | 14212.8 | Wall | 2 | 180 | 0.00111627

# IfcReinforcingBar: Rebar Bar:12mm (44)
Type - Other - Category: Structural Rebar; Family Name: Rebar Bar
Type - Construction - Deformation: Deformed
Type - Dimensions - Bar Diameter: 12 mm; Maximum Bend Radius: 18000 mm; Model Bar Diameter: 12 mm; Standard Bend Diameter: 80 mm; Standard Hook Bend Diameter: 80 mm; Stirrup/Tie Bend Diameter: 50 mm
Type - Identity Data - Type Name: 12mm
Type - Materials and Finishes - Material: Steel Rebar - B500A, B or C
Material: Steel Rebar - B500A, B or C
Pset_ElementComponentCommon - Reference: 12mm; sets with these values: 2
Rebar Schedule - Bar Diameter: 12 mm; Deformation: Deformed; Family: Rebar Bar; Family and Type: Rebar Bar: 12mm; G: 0 mm; Geometry: Shape Driven; Material: Steel Rebar - B500A, B or C
Other - Family: Rebar Bar; Family and Type: Rebar Bar: 12mm; Type: 12mm; Type Id: 374903
Construction - Geometry: Shape Driven; Hook Rotation At End: 0 deg; Hook Rotation At Start: 0 deg; Modified Rebar Set: no; Override Hook Lengths: no; Rebar Constraint Status: Enabled; Staggered Set: no
Dimensions - G: 0 mm; H: 0 mm; J: 0 mm
Phasing - Phase Created: New Construction
Rebar Set - Distribution Type: Uniform; Layout Rule: Number with Spacing
Name (Rebar Bar:12mm :...) | In | Rebar Schedule, A (mm) = Dimensions, A (mm) | Rebar Schedule, B (mm) = Dimensions, B (mm) | Rebar Schedule, Bar Length (mm) = Dimensions, Bar Length (mm) = Maximum Bar Length (mm) = Minimum Bar Length (mm) | Rebar Schedule, C (mm) = Dimensions, C (mm) | Rebar Schedule, D (mm) = Dimensions, D (mm) | Rebar Schedule, E (mm) = Dimensions, E (mm) | Rebar Schedule, F (mm) = Dimensions, F (mm) | Rebar Schedule, H1 (mm) = Rebar Schedule, H2 (mm) = Dimensions, H1 (mm) = Dimensions, H2 (mm) | Bend Diameter (mm) | Maximum Rebar Number = Minimum Rebar Number = Rebar Number | Schedule Mark | Shape | Style | Length of each bar (mm) | R (mm) | Total Bar Length (mm) | Host Category | Quantity = Quantity By Rebar Set | Spacing (mm) | Estimated Reinforcement Volume (m3) = Reinforcement Volume (m3)
 Shape 21:374509 | Level -03 | 388 | 920 | 1632.51 | 388 | 0 | 0 | 0 | 0 | 80 | 2 | 1 | 21 | Standard | 1632 | 0 | 8162.57 | Structural Foundation | 5 | 200 | 0.000923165
 Shape 21:374615 | Level -03 | 399.65 | 919.3 | 1655.11 | 399.65 | 0 | 0 | 0 | 0 | 80 | 1 | 1 | 21 | Standard | 1654.6 | 0 | 8275.57 | Structural Foundation | 5 | 200 | 0.000935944
 Shape 21:375851 | Level -03 | 600 | 720 | 1856.51 | 600 | 0 | 0 | 0 | 0 | 80 | 4 | 2 | 21 | Standard | 1856 | 0 | 120673 | Structural Foundation | 65 | 200 | 0.0136478
 Shape 52:380476 | Level -03 | 925 | 420 | 2830.17 | 109 | 109 | 1180 | 1000 | 108.042 | 50 | 20 | 1 | 52 | Stirrup / Tie | 2834.5 | 0 | 8490.5 | Structural Foundation | 3 | 150 | 0.000960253 | Rebar Schedule - Hook At End: Stirrup/Tie Seismic - 135 deg.; Hook At Start: Stirrup/Tie Seismic - 135 deg.; Construction - Hook At End: Stirrup/Tie Seismic - 135 deg.; Hook At Start: Stirrup/Tie Seismic - 135 deg.; Stirrup/Tie Attachment: Interior Face of Cover Reference; Dimensions - Standard Bend Diameter: 50 mm
 Shape 52:381113 | Level -03 | 923 | 420 | 2826.17 | 109 | 109 | 1180 | 1000 | 108.042 | 50 | 13 | 1 | 52 | Stirrup / Tie | 2830.5 | 0 | 5652.34 | Structural Foundation | 2 | 200 | 0.000639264 | Rebar Schedule - Hook At End: Stirrup/Tie Seismic - 135 deg.; Hook At Start: Stirrup/Tie Seismic - 135 deg.; Construction - Hook At End: Stirrup/Tie Seismic - 135 deg.; Hook At Start: Stirrup/Tie Seismic - 135 deg.; Stirrup/Tie Attachment: Interior Face of Cover Reference; Dimensions - Standard Bend Diameter: 50 mm
 Shape 12:383577 | Level -02 | 6320 | 120 | 6403.96 | 0 | 0 | 0 | 0 | 0 | 80 | 21 | 3 | 12 | Standard | 6404.1 | 50 | 416258 | Structural Foundation | 65 | 200 | 0.0470776
 Shape 21:383880 | Level -02 | 120 | 6621 | 6797.51 | 120 | 0 | 0 | 0 | 0 | 80 | 52 | 3 | 21 | Standard | 6797 | 0 | 13595 | Structural Foundation | 2 | 200 | 0.00153756
 Shape 21:383941 | Level -02 | 120 | 6621 | 6827.51 | 150 | 0 | 0 | 0 | 0 | 80 | 54 | 3 | 21 | Standard | 6827 | 0 | 13655 | Structural Foundation | 2 | 200 | 0.00154435
 Shape 21:383959 | Level -02 | 120 | 6621 | 6797.51 | 120 | 0 | 0 | 0 | 0 | 80 | 52 | 3 | 21 | Standard | 6797 | 0 | 13595 | Structural Foundation | 2 | 200 | 0.00153756
 Shape 21:383973 | Level -02 | 120 | 6621 | 6797.51 | 120 | 0 | 0 | 0 | 0 | 80 | 52 | 3 | 21 | Standard | 6797 | 0 | 13595 | Structural Foundation | 2 | 200 | 0.00153756
 Shape 12:384594 | Level -02 | 7000 | 150 | 7113.96 | 0 | 0 | 0 | 0 | 0 | 80 | 24 | 3 | 12 | Standard | 7114.1 | 50 | 220533 | Structural Foundation | 31 | 200 | 0.0249417
 Shape 12:385067 | Level -02 | 7000 | 120 | 7083.96 | 0 | 0 | 0 | 0 | 0 | 80 | 25 | 3 | 12 | Standard | 7084.1 | 50 | 219603 | Structural Foundation | 31 | 200 | 0.0248365
 Shape 21:385219 | Level -02 | 898 | 150 | 1882.51 | 898 | 0 | 0 | 0 | 0 | 80 | 27 | 3 | 21 | Standard | 1882 | 0 | 122363 | Structural Foundation | 65 | 200 | 0.013839
 Shape 21:385727 | Level -03 | 388 | 920 | 1632.51 | 388 | 0 | 0 | 0 | 0 | 80 | 2 | 1 | 21 | Standard | 1632 | 0 | 8162.57 | Structural Foundation | 5 | 200 | 0.000923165
 Shape 21:385729 | Level -03 | 410 | 919.3 | 1675.81 | 410 | 0 | 0 | 0 | 0 | 80 | 28 | 1 | 21 | Standard | 1675.3 | 0 | 8379.07 | Structural Foundation | 5 | 200 | 0.00094765
 Shape 52:385732 | Level -03 | 925 | 420 | 2830.17 | 109 | 109 | 1180 | 1000 | 108.042 | 50 | 20 | 1 | 52 | Stirrup / Tie | 2834.5 | 0 | 8490.5 | Structural Foundation | 3 | 150 | 0.000960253 | Rebar Schedule - Hook At End: Stirrup/Tie Seismic - 135 deg.; Hook At Start: Stirrup/Tie Seismic - 135 deg.; Construction - Hook At End: Stirrup/Tie Seismic - 135 deg.; Hook At Start: Stirrup/Tie Seismic - 135 deg.; Stirrup/Tie Attachment: Interior Face of Cover Reference; Dimensions - Standard Bend Diameter: 50 mm
 Shape 52:385733 | Level -03 | 923 | 420 | 2826.17 | 109 | 109 | 1180 | 1000 | 108.042 | 50 | 13 | 1 | 52 | Stirrup / Tie | 2830.5 | 0 | 5652.34 | Structural Foundation | 2 | 200 | 0.000639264 | Rebar Schedule - Hook At End: Stirrup/Tie Seismic - 135 deg.; Hook At Start: Stirrup/Tie Seismic - 135 deg.; Construction - Hook At End: Stirrup/Tie Seismic - 135 deg.; Hook At Start: Stirrup/Tie Seismic - 135 deg.; Stirrup/Tie Attachment: Interior Face of Cover Reference; Dimensions - Standard Bend Diameter: 50 mm
 Shape 21:385756 | Level -03 | 388 | 920 | 1632.51 | 388 | 0 | 0 | 0 | 0 | 80 | 2 | 1 | 21 | Standard | 1632 | 0 | 8162.57 | Structural Foundation | 5 | 200 | 0.000923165
 Shape 21:385757 | Level -03 | 410 | 919.3 | 1675.81 | 410 | 0 | 0 | 0 | 0 | 80 | 28 | 1 | 21 | Standard | 1675.3 | 0 | 8379.07 | Structural Foundation | 5 | 200 | 0.00094765
 Shape 52:385759 | Level -03 | 925 | 420 | 2830.17 | 109 | 109 | 1180 | 1000 | 108.042 | 50 | 20 | 1 | 52 | Stirrup / Tie | 2834.5 | 0 | 8490.5 | Structural Foundation | 3 | 150 | 0.000960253 | Rebar Schedule - Hook At End: Stirrup/Tie Seismic - 135 deg.; Hook At Start: Stirrup/Tie Seismic - 135 deg.; Construction - Hook At End: Stirrup/Tie Seismic - 135 deg.; Hook At Start: Stirrup/Tie Seismic - 135 deg.; Stirrup/Tie Attachment: Interior Face of Cover Reference; Dimensions - Standard Bend Diameter: 50 mm
 Shape 52:385760 | Level -03 | 923 | 420 | 2826.17 | 109 | 109 | 1180 | 1000 | 108.042 | 50 | 13 | 1 | 52 | Stirrup / Tie | 2830.5 | 0 | 5652.34 | Structural Foundation | 2 | 200 | 0.000639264 | Rebar Schedule - Hook At End: Stirrup/Tie Seismic - 135 deg.; Hook At Start: Stirrup/Tie Seismic - 135 deg.; Construction - Hook At End: Stirrup/Tie Seismic - 135 deg.; Hook At Start: Stirrup/Tie Seismic - 135 deg.; Stirrup/Tie Attachment: Interior Face of Cover Reference; Dimensions - Standard Bend Diameter: 50 mm
 Shape 21:385779 | Level -03 | 388 | 920 | 1632.51 | 388 | 0 | 0 | 0 | 0 | 80 | 2 | 1 | 21 | Standard | 1632 | 0 | 8162.57 | Structural Foundation | 5 | 200 | 0.000923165
 Shape 21:385780 | Level -03 | 410 | 919.3 | 1675.81 | 410 | 0 | 0 | 0 | 0 | 80 | 28 | 1 | 21 | Standard | 1675.3 | 0 | 8379.07 | Structural Foundation | 5 | 200 | 0.00094765
 Shape 52:385782 | Level -03 | 925 | 420 | 2830.17 | 109 | 109 | 1180 | 1000 | 108.042 | 50 | 20 | 1 | 52 | Stirrup / Tie | 2834.5 | 0 | 8490.5 | Structural Foundation | 3 | 150 | 0.000960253 | Rebar Schedule - Hook At End: Stirrup/Tie Seismic - 135 deg.; Hook At Start: Stirrup/Tie Seismic - 135 deg.; Construction - Hook At End: Stirrup/Tie Seismic - 135 deg.; Hook At Start: Stirrup/Tie Seismic - 135 deg.; Stirrup/Tie Attachment: Interior Face of Cover Reference; Dimensions - Standard Bend Diameter: 50 mm
 Shape 52:385783 | Level -03 | 923 | 420 | 2826.17 | 109 | 109 | 1180 | 1000 | 108.042 | 50 | 13 | 1 | 52 | Stirrup / Tie | 2830.5 | 0 | 5652.34 | Structural Foundation | 2 | 200 | 0.000639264 | Rebar Schedule - Hook At End: Stirrup/Tie Seismic - 135 deg.; Hook At Start: Stirrup/Tie Seismic - 135 deg.; Construction - Hook At End: Stirrup/Tie Seismic - 135 deg.; Hook At Start: Stirrup/Tie Seismic - 135 deg.; Stirrup/Tie Attachment: Interior Face of Cover Reference; Dimensions - Standard Bend Diameter: 50 mm
 Shape 00:386488 | Level -01 | 5166 | 0 | 5166 | 0 | 0 | 0 | 0 | 0 | 80 | 30 | 4 | 00 | Standard | 5166 | 0 | 129150 | Wall | 25 | 200 | 0.0146065
 Shape 00:387049 | Level -01 | 5166 | 0 | 5166 | 0 | 0 | 0 | 0 | 0 | 80 | 30 | 4 | 00 | Standard | 5166 | 0 | 129150 | Wall | 25 | 200 | 0.0146065
 Shape 00:387192 | Level -01 | 5166 | 0 | 5166 | 0 | 0 | 0 | 0 | 0 | 80 | 30 | 4 | 00 | Standard | 5166 | 0 | 25830 | Wall | 5 | 200 | 0.0029213
 Shape 00:387269 | Level -01 | 5166 | 0 | 5166 | 0 | 0 | 0 | 0 | 0 | 80 | 30 | 4 | 00 | Standard | 5166 | 0 | 25830 | Wall | 5 | 200 | 0.0029213
 Shape 21:387684 | Level 01 | 720 | 226 | 1602.51 | 720 | 0 | 0 | 0 | 0 | 80 | 41 | 4 | 21 | Standard | 1602 | 0 | 56088 | Wall | 35 | 200 | 0.0063434
 Shape 00:387829 | Level 01 | 1945.62 | 0 | 1945.62 | 0 | 0 | 0 | 0 | 0 | 80 | 32 | 4 | 00 | Standard | 1945.62 | 0 | 68096.9 | Wall | 35 | 200 | 0.00770157
 Shape 00:387992 | Level 01 | 1945.62 | 0 | 1945.62 | 0 | 0 | 0 | 0 | 0 | 80 | 32 | 4 | 00 | Standard | 1945.62 | 0 | 68096.9 | Wall | 35 | 200 | 0.00770157
 Shape 52:388664 | Level -01 | 950 | 250 | 2540.17 | 109 | 109 | 1180 | 1000 | 108.042 | 50 | 37 | 4 | 52 | Stirrup / Tie | 2544.5 | 0 | 40642.7 | Wall | 16 | 200 | 0.00459658 | Rebar Schedule - Hook At End: Stirrup/Tie Seismic - 135 deg.; Hook At Start: Stirrup/Tie Seismic - 135 deg.; Construction - Hook At End: Stirrup/Tie Seismic - 135 deg.; Hook At Start: Stirrup/Tie Seismic - 135 deg.; Stirrup/Tie Attachment: Interior Face of Cover Reference; Dimensions - Standard Bend Diameter: 50 mm
 Shape 00:388697 | Level 01 | 8750 | 0 | 8750 | 0 | 0 | 0 | 0 | 0 | 80 | 40 | 4 | 00 | Standard | 8750 | 0 | 78750 | Wall | 9 | 200 | 0.00890642
 Shape 00:389438 | Level -01 | 4950 | 0 | 4950 | 0 | 0 | 0 | 0 | 0 | 80 | 39 | 4 | 00 | Standard | 4950 | 0 | 128700 | Wall | 26 | 200 | 0.0145556
 Shape 00:391324 | Level 01 | 8750 | 0 | 8750 | 0 | 0 | 0 | 0 | 0 | 80 | 40 | 4 | 00 | Standard | 8750 | 0 | 78750 | Wall | 9 | 200 | 0.00890642
 Shape 00:391373 | Level -01 | 4950 | 0 | 4950 | 0 | 0 | 0 | 0 | 0 | 80 | 39 | 4 | 00 | Standard | 4950 | 0 | 128700 | Wall | 26 | 200 | 0.0145556
 Shape 00:392552 | Level 00 | 1500 | 0 | 1500 | 0 | 0 | 0 | 0 | 0 | 80 | 44 | 4 | 00 | Standard | 1500 | 0 | 4500 | Wall | 3 | 100 | 0.000508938
 Shape 00:393302 | Level 00 | 1500 | 0 | 1500 | 0 | 0 | 0 | 0 | 0 | 80 | 44 | 4 | 00 | Standard | 1500 | 0 | 4500 | Wall | 3 | 100 | 0.000508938
 Shape 00:393427 | Level 00 | 1500 | 0 | 1500 | 0 | 0 | 0 | 0 | 0 | 80 | 44 | 4 | 00 | Standard | 1500 | 0 | 4500 | Wall | 3 | 100 | 0.000508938
 Shape 00:393428 | Level 00 | 1500 | 0 | 1500 | 0 | 0 | 0 | 0 | 0 | 80 | 44 | 4 | 00 | Standard | 1500 | 0 | 4500 | Wall | 3 | 100 | 0.000508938
 Shape 00:394260 | Level -03 | 12000 | 0 | 12000 | 0 | 0 | 0 | 0 | 0 | 80 | 47 | 2 | 00 | Standard | 12000 | 0 | 48000 | Structural Foundation | 4 | 200 | 0.00542867
 Shape 12:396877 | Level -02 | 7059 | 138 | 7160.96 | 0 | 0 | 0 | 0 | 0 | 80 | 51 | 3 | 12 | Standard | 7161.1 | 50 | 14321.9 | Structural Foundation | 2 | 180 | 0.00161977
 Shape 12:397623 | Level -02 | 7059 | 138 | 7160.96 | 0 | 0 | 0 | 0 | 0 | 80 | 51 | 3 | 12 | Standard | 7161.1 | 50 | 14321.9 | Wall | 2 | 180 | 0.00161977

# IfcReinforcingBar: Rebar Bar:16mm (3)
Type - Other - Category: Structural Rebar; Family Name: Rebar Bar
Type - Construction - Deformation: Deformed
Type - Dimensions - Bar Diameter: 16 mm; Maximum Bend Radius: 18000 mm; Model Bar Diameter: 16 mm; Standard Bend Diameter: 80 mm; Standard Hook Bend Diameter: 80 mm; Stirrup/Tie Bend Diameter: 50 mm
Type - Identity Data - Type Name: 16mm
Type - Materials and Finishes - Material: Steel Rebar - B500A, B or C
Material: Steel Rebar - B500A, B or C
Pset_ElementComponentCommon - Reference: 16mm; sets with these values: 2
Rebar Schedule - D: 0 mm; Deformation: Deformed; E: 0 mm; F: 0 mm; G: 0 mm; Geometry: Shape Driven; H1: 0 mm; H2: 0 mm; Bar Diameter: 16 mm; Family: Rebar Bar; Family and Type: Rebar Bar: 16mm; Material: Steel Rebar - B500A, B or C
Other - Family: Rebar Bar; Family and Type: Rebar Bar: 16mm; Type: 16mm; Type Id: 388021
Construction - Geometry: Shape Driven; Hook Rotation At End: 0 deg; Hook Rotation At Start: 0 deg; Modified Rebar Set: no; Override Hook Lengths: no; Rebar Constraint Status: Enabled; Shape: 21; Staggered Set: no; Style: Standard; Bend Diameter: 80 mm
Dimensions - D: 0 mm; E: 0 mm; F: 0 mm; G: 0 mm; H1: 0 mm; H2: 0 mm; H: 0 mm; J: 0 mm; R: 0 mm
Phasing - Phase Created: New Construction
Rebar Set - Distribution Type: Uniform
Name (Rebar Bar:16mm : Shape 21:...) | In | Rebar Schedule, A (mm) = Rebar Schedule, C (mm) = Dimensions, A (mm) = Dimensions, C (mm) | Rebar Schedule, B (mm) = Dimensions, B (mm) | Rebar Schedule, Bar Length (mm) = Dimensions, Bar Length (mm) = Maximum Bar Length (mm) = Minimum Bar Length (mm) | Maximum Rebar Number = Minimum Rebar Number = Rebar Number | Schedule Mark | Length of each bar (mm) | Total Bar Length (mm) | Host Category | Layout Rule | Quantity = Quantity By Rebar Set | Spacing (mm) | Estimated Reinforcement Volume (m3) = Reinforcement Volume (m3)
377274 | Level -03 | 1720 | 250 | 3616.8 | 33 | 2 | 3618 | 90419.9 | Structural Foundation | Number with Spacing | 25 | 200 | 0.01818
378933 | Level -03 | 1720 | 250 | 3616.8 | 33 | 2 | 3618 | 18084 | Structural Foundation | Number with Spacing | 5 | 200 | 0.003636
388116 | Level 01 | 308 | 8718.64 | 9261.44 | 34 | 4 | 9262.64 | 27784.3 | Wall | Fixed Number | 3 |  | 0.00558637

# IfcSlab: Floor:Blinding Concrete 80mm (6)
Type - PredefinedType: FLOOR; Material: Concrete - Cast-in-Place Concrete 80 mm
Type - Other - Category: Floors; Family Name: Floor
Type - Construction - Default Thickness: 80 mm; Function: Interior
Type - Graphics - Coarse Scale Fill Color: 0
Type - Identity Data - Type Name: Blinding Concrete 80mm
Type - Materials and Finishes - Structural Material: Concrete - Cast-in-Place Concrete
Type - Analytical Properties - Absorptance: 0.7; Roughness: 3
Pset_EnvironmentalImpactIndicators - Reference: Blinding Concrete 80mm; sets with these values: 2
Pset_SlabCommon - IsExternal: no; LoadBearing: yes; Reference: Blinding Concrete 80mm; PitchAngle: 0 deg
Other - Family: Floor; Family and Type: Floor: Blinding Concrete 80mm; Type: Blinding Concrete 80mm; Type Id: 487924
Constraints - Height Offset From Level: 0 mm; Related to Mass: no; Room Bounding: yes
Dimensions - Core Thickness: 80 mm; Thickness: 80 mm
Identity Data - Has Association: no
Phasing - Phase Created: New Construction
Structural - Rebar Cover - Other Faces: Rebar Cover 1 <25 mm>; Structural: yes; Rebar Cover - Bottom Face: Rebar Cover 1 <25 mm>; Rebar Cover - Top Face: Rebar Cover 1 <25 mm>
Name (Floor:Blinding Concrete 80mm:...) | In | Level | Area (m2) | Elevation at Bottom (mm) = Elevation at Bottom Core (mm) = Elevation at Bottom Survey (mm) | Elevation at Top (mm) = Elevation at Top Core (mm) = Elevation at Top Survey (mm) | Perimeter (mm) | Volume (m3)
487904 | Level -02 | Level -02 | 75.56 | -480 | -400 | 42240 | 6.0448
489091 | Level -03 | Level -03 | 14.4 | -1280 | -1200 | 43600 | 1.152
489091:2 | Level -03 | Level -03 | 14.4 | -1280 | -1200 | 43600 | 1.152
489091:3 | Level -03 | Level -03 | 14.4 | -1280 | -1200 | 43600 | 1.152
489091:4 | Level -03 | Level -03 | 14.4 | -1280 | -1200 | 43600 | 1.152
489091:5 | Level -03 | Level -03 | 14.4 | -1280 | -1200 | 43600 | 1.152

# IfcSlab: Floor:Gravel 200mm, Floor:Gravel 200mm:488938
In: Level -02
Type - PredefinedType: FLOOR; Material: Gravel 200 mm
Type - Other - Category: Floors; Family Name: Floor
Type - Construction - Function: Interior; Default Thickness: 200 mm
Type - Graphics - Coarse Scale Fill Color: 0
Type - Identity Data - Type Name: Gravel 200mm
Type - Materials and Finishes - Structural Material: Gravel
Type - Analytical Properties - Absorptance: 0.7; Roughness: 3; Heat Transfer Coefficient (U): 1.8 kg/K/s3; Thermal Mass: 309120 kg/K/s2; Thermal Resistance (R): 0.555556 s3*K/kg
Type - Pset_SlabCommon - ThermalTransmittance: 1.8 kg/K/s3
Pset_EnvironmentalImpactIndicators - Reference: Gravel 200mm; sets with these values: 2
Pset_SlabCommon - IsExternal: no; LoadBearing: yes; PitchAngle: 0 deg; Reference: Gravel 200mm
Other - Family: Floor; Family and Type: Floor: Gravel 200mm; Type: Gravel 200mm; Type Id: 488991
Constraints - Level: Level -02; Related to Mass: no; Room Bounding: yes; Height Offset From Level: -80 mm
Dimensions - Area: 75.56 m2; Core Thickness: 200 mm; Elevation at Bottom: -680 mm; Elevation at Bottom Core: -680 mm; Elevation at Bottom Survey: -680 mm; Elevation at Top: -480 mm; Elevation at Top Core: -480 mm; Elevation at Top Survey: -480 mm; Perimeter: 42240 mm; Thickness: 200 mm; Volume: 15.112 m3
Identity Data - Has Association: no
Phasing - Phase Created: New Construction
Structural - Rebar Cover - Other Faces: Rebar Cover 1 <25 mm>; Structural: yes; Rebar Cover - Bottom Face: Rebar Cover 1 <25 mm>; Rebar Cover - Top Face: Rebar Cover 1 <25 mm>

# IfcWall: Basic Wall:Generic - 300mm, Basic Wall:Generic - 300mm:356160
In: Level -02
Type - PredefinedType: STANDARD; Material: Concrete - Cast-in-Place Concrete 300 mm
Type - Other - Category: Walls; Family Name: Basic Wall
Type - Construction - Function: Exterior; Width: 300 mm; Wrapping at Inserts: Do not wrap
Type - Graphics - Coarse Scale Fill Color: 0
Type - Identity Data - Type Name: Generic - 300mm
Type - Materials and Finishes - Structural Material: Concrete - Cast-in-Place Concrete
Type - Analytical Properties - Absorptance: 0.7; Roughness: 3
Pset_EnvironmentalImpactIndicators - Reference: Generic - 300mm; sets with these values: 2
Pset_WallCommon - Reference: Generic - 300mm; IsExternal: yes; LoadBearing: yes; ExtendToStructure: no
Other - Family: Basic Wall; Family and Type: Basic Wall: Generic - 300mm; Type: Generic - 300mm; Type Id: 6291
Constraints - Base Constraint: Level -02; Base Extension Distance: 0 mm; Base is Attached: no; Base Offset: 0 mm; Location Line: Wall Centerline; Related to Mass: no; Room Bounding: yes; Top Constraint: Up to level: Level -02; Top Extension Distance: 0 mm; Top is Attached: no; Top Offset: 5400 mm; Unconnected Height: 5400 mm
Dimensions - Area: 47.8 m2; Length: 13000 mm; Volume: 14.34 m3
Identity Data - Has Association: no
Phasing - Phase Created: New Construction
Structural - Estimated Reinforcement Volume: 0.133566 m3; Rebar Cover - Exterior Face: Rebar Cover 1 <25 mm>; Rebar Cover - Interior Face: Rebar Cover 1 <25 mm>; Rebar Cover - Other Faces: Rebar Cover 1 <25 mm>; Structural: yes; Structural Usage: Bearing
Cross-Section Definition - Cross-Section: Vertical

# Material: Concrete - Cast-in-Place Concrete
Identity - Category: Concrete; Class: Concrete
Structural - Name: Normal Weight Concrete - 35 MPa; Type: Concrete; Behavior: Isotropic; TensileStrength: 448.159 Pa; ConcreteCompression: 35000000 Pa; ShearStrengthModification: 1; ThermallyTreated: no
Pset_MaterialCommon - MassDensity: 2406.53 kg/m3
Pset_MaterialMechanical - YoungModulus: 29910000000 kg/s2/m; ShearModulus: 12463000000 kg/s2/m; PoissonRatio: 0.2; ThermalExpansionCoefficient: 0.0000099 1/K
Pset_MaterialSteel - YieldStress: 344.738 Pa
Other - Category: Materials
Materials and Finishes - Color: 12632256; Glow: no; Material Type: Concrete; Name: Concrete - Cast-in-Place Concrete; Shininess: 128; Smoothness: 50; Transparency: 0

# Material: Concrete, Cast In Situ
Identity - Category: Concrete; Class: Concrete
Structural - ShearStrengthModification: 1; Name: Concrete 10 MPa; Description: Concrete f'c=10 MPa; Keywords: structural:concrete; Type: Concrete; SubClass: Standard; Source: Autodesk; Behavior: Isotropic; TensileStrength: 1000000 Pa; ConcreteCompression: 10000000 Pa; ThermallyTreated: no
Thermal - Name: Concrete; Description: Concrete, stone aggregate; Keywords: thermal:solid; Type: Solid; SubClass: Concrete; Source: Autodesk; Density: 2300 kg/m3; Emissivity: 0.95; Behavior: Isotropic; TransmitsLight: no; Permeability: 0 s/m; Reflectivity: 0; ElectricalResistivity: 2000000 kg*m3/s3/A2
Pset_MaterialCommon - Porosity: 0.001; MassDensity: 2406.45 kg/m3
Pset_MaterialMechanical - YoungModulus: 20500000000 kg/s2/m; ShearModulus: 9430000000 kg/s2/m; PoissonRatio: 0.2; ThermalExpansionCoefficient: 0.00001 1/K
Pset_MaterialSteel - YieldStress: 1000000 Pa
Pset_MaterialThermal - SpecificHeatCapacity: 657 m2/K/s2; ThermalConductivity: 1.046
Other - Category: Materials
Identity Data - Cost: 0; Description: physical material
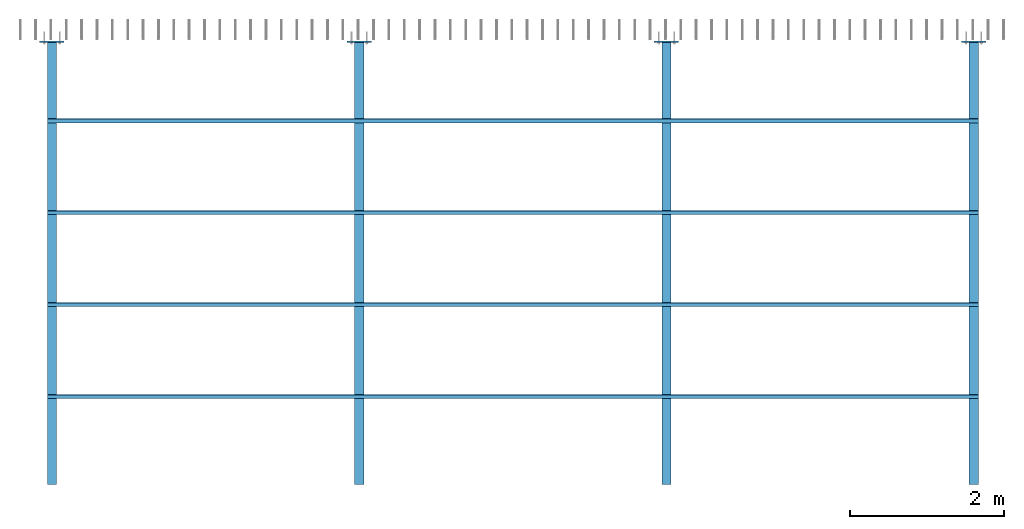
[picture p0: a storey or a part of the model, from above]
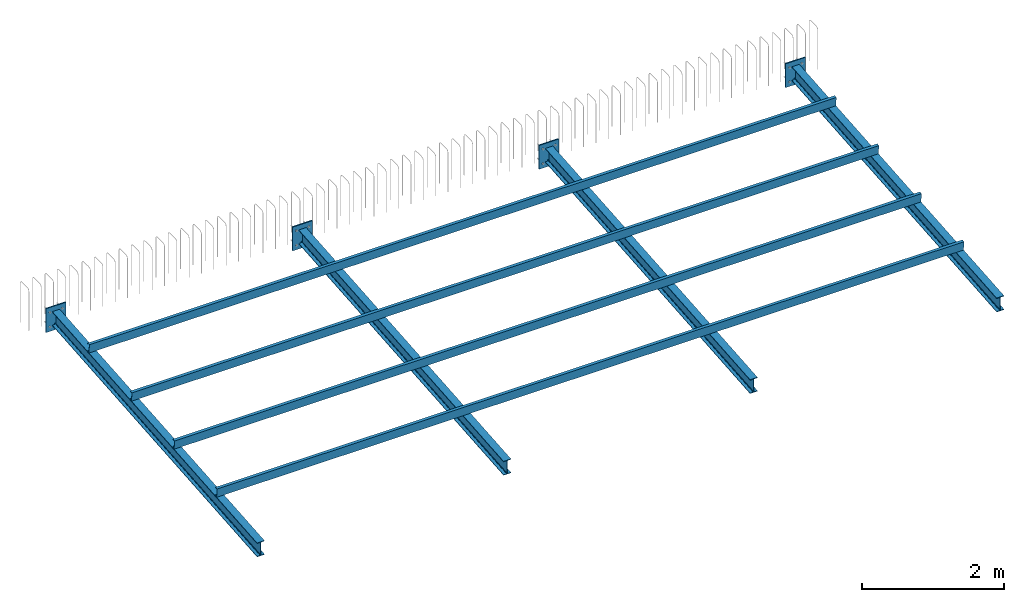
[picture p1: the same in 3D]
Properties of the parts of a building model (IFC4X3_ADD2), part 2 of 2

Materials and Finishes - Glow: no; Material Type: Concrete; Transparency: 0; Color: 12632256; Name: Concrete, Cast In Situ; Shininess: 128; Smoothness: 50

# Material: Steel Rebar - B500A, B or C
Identity - Category: Unassigned; Class: Metal
Structural - Name: B500A, B or C_Rebar; Type: Metal; Behavior: Isotropic; TensileStrength: 500000000 Pa; ThermallyTreated: no
Pset_MaterialCommon - MassDensity: 7852.83 kg/m3
Pset_MaterialMechanical - YoungModulus: 210000000000 kg/s2/m; ShearModulus: 0 kg/s2/m; PoissonRatio: 0.3; ThermalExpansionCoefficient: 0 1/K
Pset_MaterialSteel - YieldStress: 500000000 Pa
Other - Category: Materials
Identity Data - Cost: 0
Materials and Finishes - Glow: no; Transparency: 0; Color: 16250871; Material Type: Steel; Name: Steel Rebar - B500A, B or C; Shininess: 64; Smoothness: 50

# Material: Metal - Steel 50-355
Identity - Category: Metal; Class: Metal
Structural - Name: STEEL 50-355; Type: Metal; Behavior: Isotropic; TensileStrength: 500000000 Pa; ThermallyTreated: no
Pset_MaterialCommon - MassDensity: 7852.83 kg/m3
Pset_MaterialMechanical - YoungModulus: 205000000000 kg/s2/m; ShearModulus: 80000000000 kg/s2/m; PoissonRatio: 0.3; ThermalExpansionCoefficient: 0.000012 1/K
Pset_MaterialSteel - YieldStress: 355000000 Pa
Other - Category: Materials
Materials and Finishes - Glow: no; Transparency: 0; Material Type: Steel; Color: 16250871; Name: Metal - Steel 50-355; Shininess: 128; Smoothness: 50

# Material: Lindab_000_Galvanized
Identity - Class: Metal
Other - Category: Materials
Identity Data - Cost: 0; Description: Galvanized steel
Materials and Finishes - Glow: no; Transparency: 0; Color: 7895160; Name: Lindab_000_Galvanized; Shininess: 64; Smoothness: 50

# Material: Gravel
Identity - Category: Misc; Class: Generic
Structural - Name: Gravel; Description: Basic structural asset.; Keywords: stone:ballast:structural:basic; Type: Basic; Behavior: Isotropic
Thermal - Permeability: 0 s/m; Reflectivity: 0; Name: Gravel; Description: Gravel; Keywords: Crushed Stone:ballast:aggregate:thermal:solid; Type: Solid; SubClass: Earth; Source: Autodesk; Density: 1840 kg/m3; Emissivity: 0.9; Behavior: Isotropic; TransmitsLight: no; ElectricalResistivity: 15000 kg*m3/s3/A2
Pset_MaterialCommon - Porosity: 0.001; MassDensity: 1840 kg/m3
Pset_MaterialThermal - SpecificHeatCapacity: 840 m2/K/s2; ThermalConductivity: 0.36
Other - Category: Materials
Identity Data - Cost: 0; Description: Crushed stone or gravel
Materials and Finishes - Glow: no; Transparency: 0; Color: 7895160; Material Type: Other; Name: Gravel; Shininess: 64; Smoothness: 50

# Material: Structural Steel - S235
Identity - Category: Metal; Class: Metal
Structural - Name: S235; Type: Metal; Behavior: Isotropic; TensileStrength: 360000000 Pa; ThermallyTreated: no
Pset_MaterialCommon - MassDensity: 8004.8 kg/m3
Pset_MaterialMechanical - YoungModulus: 210000000000 kg/s2/m; ShearModulus: 81000000000 kg/s2/m; PoissonRatio: 0.3; ThermalExpansionCoefficient: 0.000012 1/K
Pset_MaterialSteel - YieldStress: 240000000 Pa
Other - Category: Materials
Identity Data - Cost: 0
Materials and Finishes - Glow: no; Transparency: 0; Material Type: Steel; Color: 12172221; Name: Structural Steel - S235; Shininess: 64; Smoothness: 50
